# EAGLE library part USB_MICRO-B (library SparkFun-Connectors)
USB Type Micro-B Connector Male/female and PTH/SMT variants SparkFun Products: SparkFun microB USB Breakout SparkFun USB microB Plug Breakout SparkFun ESP8266 Thing

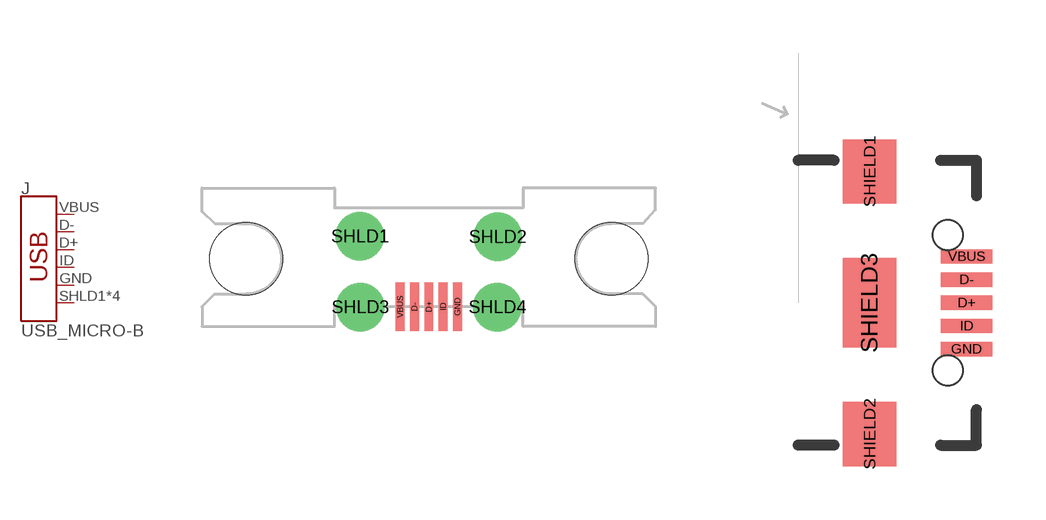
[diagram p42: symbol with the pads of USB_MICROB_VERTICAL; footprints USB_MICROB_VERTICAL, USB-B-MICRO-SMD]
Designator prefix J

## USB_MICRO-B_MALE-VERT (PROD_ID: CONN-09900)  [USB_MICROB_VERTICAL]
D+  D+
D-  D-
GND  GND  pwr
ID  ID
SHLD1  SHIELD
SHLD2  SHIELD
SHLD3  SHIELD
SHLD4  SHIELD
VBUS  VBUS  pwr

## USB_MICRO-B_FEMALE-SMT (PROD_ID: CONN-11752)  [USB-B-MICRO-SMD]
D+  D+
D-  D-
GND  GND  pwr
ID  ID
SHIELD1  SHIELD
SHIELD2  SHIELD
SHIELD3  SHIELD
VBUS  VBUS  pwr

## USB_MICRO-B_SMT (PROD_ID: CONN-09505; SF_ID: PRT-08533)  [USB-MICROB]
D+  D+
D-  D-
GND  GND  pwr
ID  ID
MT1  SHIELD
MT2  SHIELD
P$1  SHIELD
P$2  SHIELD
VBUS  VBUS  pwr

## USB_MICRO-BREDUCED_PASTE (PROD_ID: CONN-11752)  [USB-B-MICRO-SMD_RED_PASTE]
Pads as for USB-B-MICRO-SMD

## USB_MICRO-B_HALF_PTH (PROD_ID: CONN-13711; VALUE: AMP FCI 10103594-0001LF)  [USB-MICROB-PTH]
7  SHIELD
D+  D+
D-  D-
GND  GND  pwr
ID  ID
SHEILD2  SHIELD
SHIELD  SHIELD
SHIELD3  SHIELD
SHIELD4  SHIELD
SHIELD5  SHIELD
SHIELD6  SHIELD
SHIELD8  SHIELD
SHIELD9  SHIELD
SHIELD10  SHIELD
SHIELD11  SHIELD
SHIELD12  SHIELD
VBUS  VBUS  pwr

## USB_MICRO-B_FEMALE-SMT-VERT (PROD_ID: CONN-13534; VALUE: WM9734TR-ND)  [USB-B-MICRO-SMD_VERT]
D+  D+
D-  D-
GND  GND  pwr
ID  ID
P1  SHIELD
P2  SHIELD
P3  SHIELD
VBUS  VBUS  pwr

## USB_MICRO-B_HALF_PTH_MILL (PROD_ID: CONN-13711)  [USB-MICROB-PTH-MILL]
D+  D+
D-  D-
GND  GND  pwr
ID  ID
SHIELD  SHIELD
SHIELD2  SHIELD
SHIELD3  SHIELD
SHIELD4  SHIELD
SHIELD5  SHIELD
SHIELD6  SHIELD
SHIELD7  SHIELD
SHIELD8  SHIELD
SHIELD9  SHIELD
SHIELD10  SHIELD
VBUS  VBUS  pwr

## Footprint USB_MICROB_VERTICAL (pad centres in mm)
USB Micro-B Plug Connector Manufacturer part #: ZX80-B-5SA Manufacturer: Hirose Specifications: Pin count: 5 main, 4 shield Datasheet referenced for footprint Example device(s): USB_Micro-B
smd 0.4 x 2.2: D+ 0,0; D- -0.65,0; GND 1.3,0; ID 0.65,0; VBUS -1.3,0
drill 1.016 pad 2.2: SHLD1 -3.121,3.183; SHLD2 3.122,3.16; SHLD3 -3.098,-0.027; SHLD4 3.108,-0.026
hole 3.3 at -8.275,2.17
hole 3.3 at 8.275,2.17

## Footprint USB-B-MICRO-SMD (pad centres in mm)
USB - microB SMD Specifications: Pin count:5 Datasheet referenced for footprint Example device(s): USB_MICRO-B
smd 1.45 x 0.4: D+ 2.725,0; D- 2.725,0.65; GND 2.725,-1.3; ID 2.725,-0.65; VBUS 2.725,1.3
smd 1.5 x 1.8: SHIELD1 0,3.685; SHIELD2 0,-3.685
smd 1.5 x 2.5: SHIELD3 0,0
hole 0.85 at 2.2,1.9
hole 0.85 at 2.2,-1.9

## Footprint USB-MICROB (pad centres in mm)
USB Type microUSB Connector-No Bossed Pins Specifications: Pin count:5 pins, 4 shield connections Example device(s): USB_Micro-B
smd 1.4 x 0.35: D+ -2.65,0; D- -2.65,-0.65; GND -2.65,1.3; ID -2.65,0.65; VBUS -2.65,-1.3
smd 1.9 x 1.8: MT1 0,-4; MT2 0,4
smd 1.9 x 1.9: P$1 0,-1.27; P$2 0,1.27

## Footprint USB-B-MICRO-SMD_RED_PASTE (pad centres in mm)
USB - microB SMD Reduced Paste 70% paste area under D+ D- USBID pins for applications where those pins aren't required, to reduce the likelihood of bridges. Specifications: Pin count:5 Datasheet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
smd 1.45 x 0.4: D+ 2.725,0; D- 2.725,0.65; GND 2.725,-1.3; ID 2.725,-0.65; VBUS 2.725,1.3
smd 1.5 x 1.8: SHIELD1 0,3.685; SHIELD2 0,-3.685
smd 1.5 x 2.5: SHIELD3 0,0
hole 0.85 at 2.2,1.9
hole 0.85 at 2.2,-1.9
